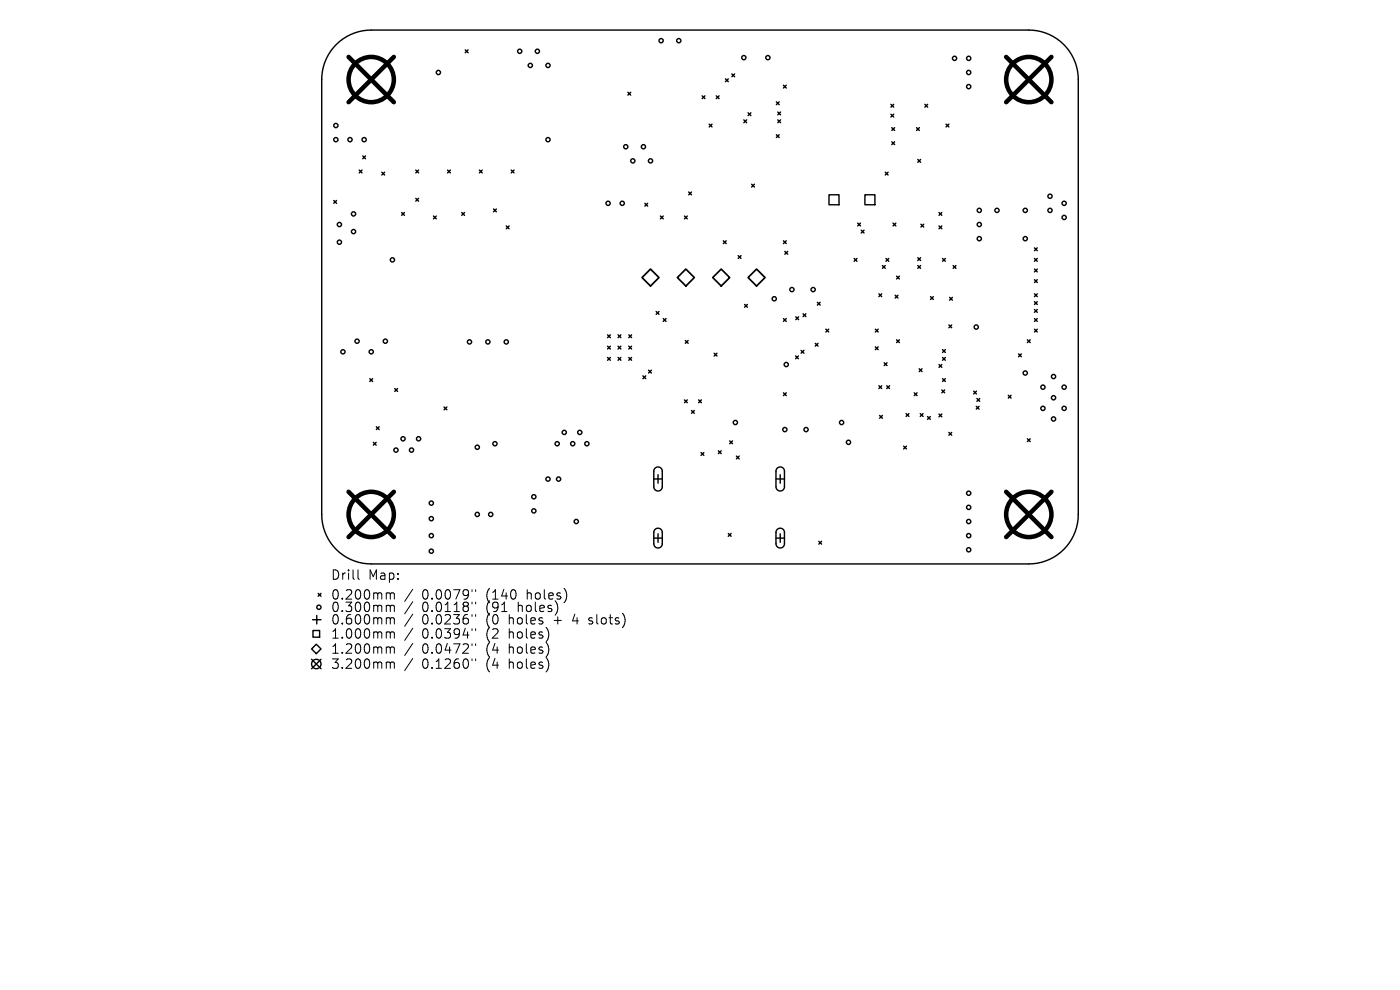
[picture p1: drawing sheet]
<svg xmlns="http://www.w3.org/2000/svg" width="297mm" height="210mm" viewBox="0 0 297 210" stroke-linecap="round" stroke-linejoin="round" font-family="sans-serif">
<defs><g id="words">
<g font-size="2.8">
<text x="70.1" y="123.3">Drill</text>
<text x="78.1" y="123.3">Map:</text>
<text x="70.1" y="127.5">0.200mm</text>
<text x="70.1" y="130.1">0.300mm</text>
<text x="89.5" y="127.5">0.0079&quot;</text>
<text x="89.5" y="130.1">0.0118&quot;</text>
<text x="103.3" y="127.5">(140</text>
<text x="103.3" y="130.1">(91</text>
<text x="110.1" y="130.1">holes)</text>
<text x="112" y="127.5">holes)</text>
<text x="70.1" y="132.8">0.600mm</text>
<text x="70.1" y="135.8">1.000mm</text>
<text x="89.5" y="132.8">0.0236&quot;</text>
<text x="89.5" y="135.8">0.0394&quot;</text>
<text x="103.3" y="132.8">(0</text>
<text x="103.3" y="135.8">(2</text>
<text x="108.2" y="132.8">holes</text>
<text x="108.2" y="135.8">holes)</text>
<text x="118" y="132.8">+</text>
<text x="122.2" y="132.8">4</text>
<text x="125.8" y="132.8">slots)</text>
<text x="70.1" y="139">1.200mm</text>
<text x="70.1" y="142.2">3.200mm</text>
<text x="89.5" y="139">0.0472&quot;</text>
<text x="89.5" y="142.2">0.1260&quot;</text>
<text x="103.3" y="139">(4</text>
<text x="103.3" y="142.2">(4</text>
<text x="108.2" y="139">holes)</text>
<text x="108.2" y="142.2">holes)</text>
</g>
</g></defs>
<g fill="none" stroke="#000" stroke-width=".3">
<path d="M71.3 9.5a10.5 10.5 0 0 1 7.5-3.1h139.5a10.5 10.5 0 0 1 10.5 10.5v92.2a10.5 10.5 0 0 1-10.5 10.5h-139.5a10.5 10.5 0 0 1-10.5-10.5v-92.2a10.5 10.5 0 0 1 3-7.4zM98.7 10.6l.6 .6M99.3 10.6l-.6 .6M133.2 19.6l.6 .6M133.8 19.6l-.6 .6M153.9 16.7l.6 .6M154.5 16.7l-.6 .6M155.3 15.7l.6 .6M155.9 15.7l-.6 .6M166.2 18.1l.6 .6M166.8 18.1l-.6 .6M76.2 36.1l.6 .6"/>
<path d="M76.8 36.1l-.6 .6M77 33.1l.6 .6M77.6 33.1l-.6 .6M81 36.5l.6 .6M81.6 36.5l-.6 .6M88.2 36.1l.6 .6M88.8 36.1l-.6 .6M95 36.1l.6 .6M95.6 36.1l-.6 .6M101.7 36.1l.6 .6M102.3 36.1l-.6 .6M108.5 36.1l.6 .6"/>
<path d="M109.1 36.1l-.6 .6M149 20.3l.6 .6M149.6 20.3l-.6 .6M150.5 26.3l.6 .6M151.1 26.3l-.6 .6M152 20.3l.6 .6M152.6 20.3l-.6 .6M157.8 25.4l.6 .6M158.4 25.4l-.6 .6M158.7 23.9l.6 .6M159.3 23.9l-.6 .6M159.5 39.1l.6 .6"/>
<path d="M160.1 39.1l-.6 .6M164.7 21.6l.6 .6M164.7 28.6l.6 .6M165 23.8l.6 .6M165 25.4l.6 .6M165.3 21.6l-.6 .6M165.3 28.6l-.6 .6M165.6 23.8l-.6 .6M165.6 25.4l-.6 .6M187.8 36.5l.6 .6M188.4 36.5l-.6 .6M189 22.1l.6 .6"/>
<path d="M189 24.2l.6 .6M189.2 27.1l.6 .6M189.2 30.1l.6 .6M189.6 22.1l-.6 .6M189.6 24.2l-.6 .6M189.8 27.1l-.6 .6M189.8 30.1l-.6 .6M194.4 27.1l.6 .6M194.7 33.8l.6 .6M195 27.1l-.6 .6M195.3 33.8l-.6 .6M196.2 22.1l.6 .6"/>
<path d="M196.8 22.1l-.6 .6M200.7 26.3l.6 .6M201.3 26.3l-.6 .6M70.8 42.5l.6 .6M71.4 42.5l-.6 .6M85.2 45.1l.6 .6M85.8 45.1l-.6 .6M88.2 42.1l.6 .6M88.8 42.1l-.6 .6M92 45.8l.6 .6M92.6 45.8l-.6 .6M98 45.1l.6 .6"/>
<path d="M98.6 45.1l-.6 .6M104.7 44.3l.6 .6M105.3 44.3l-.6 .6M107.4 47.9l.6 .6M108 47.9l-.6 .6M136.8 43.1l.6 .6M137.4 43.1l-.6 .6M140.1 45.8l.6 .6M140.7 45.8l-.6 .6M145.2 45.8l.6 .6M145.8 45.8l-.6 .6M146.1 40.7l.6 .6"/>
<path d="M146.7 40.7l-.6 .6M153.5 51.1l.6 .6M154.1 51.1l-.6 .6M156.6 54.2l.6 .6M157.2 54.2l-.6 .6M166.2 51.1l.6 .6M166.5 53.3l.6 .6M166.8 51.1l-.6 .6M167.1 53.3l-.6 .6M175.9 41.3h2.1v2.1h-2.1zM181.2 54.8l.6 .6M181.8 54.8l-.6 .6"/>
<path d="M182 47.3l.6 .6M182.6 47.3l-.6 .6M182.7 48.8l.6 .6M183.3 48.8l-.6 .6M183.5 41.3h2.1v2.1h-2.1zM187.2 56.3l.6 .6M187.8 56.3l-.6 .6M188 54.8l.6 .6M188.6 54.8l-.6 .6M189.5 47.3l.6 .6M190.1 47.3l-.6 .6M190.2 58.6l.6 .6"/>
<path d="M190.8 58.6l-.6 .6M194.7 54.7l.6 .6M194.7 56.3l.6 .6M195.3 54.7l-.6 .6M195.3 56.3l-.6 .6M195.4 47.6l.6 .6M196 47.6l-.6 .6M199.2 45.1l.6 .6M199.2 47.9l.6 .6M199.8 45.1l-.6 .6M199.8 47.9l-.6 .6M200 54.8l.6 .6"/>
<path d="M200.6 54.8l-.6 .6M202.2 56.3l.6 .6M202.8 56.3l-.6 .6M219.5 52.6l.6 .6M219.5 54.8l.6 .6M219.5 57.1l.6 .6M219.5 59.3l.6 .6M220.1 57.1l-.6 .6M220.1 52.6l-.6 .6M220.1 54.8l-.6 .6M220.1 59.3l-.6 .6M128.9 71l.6 .6"/>
<path d="M128.9 73.4l.6 .6M128.9 75.8l.6 .6M129.5 71l-.6 .6M129.5 73.4l-.6 .6M129.5 75.8l-.6 .6M131.1 71l.6 .6M131.1 73.4l.6 .6M131.1 75.8l.6 .6M131.7 71l-.6 .6M131.7 73.4l-.6 .6M131.7 75.8l-.6 .6M133.4 71l.6 .6"/>
<path d="M133.4 73.4l.6 .6M133.4 75.8l.6 .6M134 71l-.6 .6M134 73.4l-.6 .6M134 75.8l-.6 .6M136.4 79.7l.6 .6M137 79.7l-.6 .6M137.6 78.5l.6 .6M138.2 78.5l-.6 .6M139.2 66.1l.6 .6M139.8 66.1l-.6 .6M140.7 67.6l.6 .6"/>
<path d="M141.3 67.6l-.6 .6M145.4 72.2l.6 .6M146 72.2l-.6 .6M151.5 74.9l.6 .6M152.1 74.9l-.6 .6M158 64.6l.6 .6M158.6 64.6l-.6 .6M166.2 67.6l.6 .6M166.8 67.6l-.6 .6M168.8 75.5l.6 .6M168.8 67.2l.6 .6M169.4 75.5l-.6 .6"/>
<path d="M169.4 67.2l-.6 .6M170 74.3l.6 .6M170.4 66.6l.6 .6M170.6 74.3l-.6 .6M171 66.6l-.6 .6M173 72.8l.6 .6M173.4 64.1l.6 .6M173.6 72.8l-.6 .6M174 64.1l-.6 .6M175.2 69.8l.6 .6M175.8 69.8l-.6 .6M185.7 69.8l.6 .6"/>
<path d="M185.7 73.6l.6 .6M186.3 69.8l-.6 .6M186.3 73.6l-.6 .6M186.5 62.3l.6 .6M187.1 62.3l-.6 .6M187.6 77l.6 .6M188.2 77l-.6 .6M189.9 62.6l.6 .6M190.2 72.1l.6 .6M190.5 62.6l-.6 .6M190.8 72.1l-.6 .6M195 78.2l.6 .6"/>
<path d="M195.6 78.2l-.6 .6M197.4 62.9l.6 .6M198 62.9l-.6 .6M199.2 77.3l.6 .6M199.8 77.3l-.6 .6M200 75.8l.6 .6M200 74.2l.6 .6M200.6 74.2l-.6 .6M200.6 75.8l-.6 .6M201.3 68.9l.6 .6M201.5 63.1l.6 .6M201.9 68.9l-.6 .6"/>
<path d="M202.1 63.1l-.6 .6M216.1 75.1l.6 .6M216.7 75.1l-.6 .6M218 72.1l.6 .6M218.6 72.1l-.6 .6M219.5 62.3l.6 .6M219.5 64l.6 .6M219.5 65.7l.6 .6M219.5 67.6l.6 .6M219.5 69.8l.6 .6M220.1 65.7l-.6 .6M220.1 67.6l-.6 .6"/>
<path d="M220.1 62.3l-.6 .6M220.1 64l-.6 .6M220.1 69.8l-.6 .6M78.5 80.3l.6 .6M79.1 80.3l-.6 .6M79.2 93.8l.6 .6M79.8 93.8l-.6 .6M79.8 90.5l.6 .6M80.4 90.5l-.6 .6M83.7 82.4l.6 .6M84.3 82.4l-.6 .6M94.2 86.3l.6 .6"/>
<path d="M94.8 86.3l-.6 .6M139 99.3a.9 .9 0 0 1 .9-.2 .9 .9 0 0 1 .6 .9v3.3a.9 .9 0 0 1-.9 .9 .9 .9 0 0 1-.9-.9v-3.4zM145.2 84.8l.6 .6M145.8 84.8l-.6 .6M146.7 87.1l.6 .6M147.3 87.1l-.6 .6M148.2 84.8l.6 .6M148.7 96l.6 .6M148.8 84.8l-.6 .6M149.3 96l-.6 .6M152.4 95.6l.6 .6M153 95.6l-.6 .6"/>
<path d="M154.8 93.5l.6 .6M155.4 93.5l-.6 .6M156.2 96.7l.6 .6M156.8 96.7l-.6 .6M164.9 99.3a.9 .9 0 0 1 1-.2 .9 .9 0 0 1 .5 .9v3.3a.9 .9 0 0 1-.9 .9 .9 .9 0 0 1-.9-.9v-3.4zM166.2 83.3l.6 .6M166.8 83.3l-.6 .6M186.5 81.8l.6 .6M186.6 88.1l.6 .6M187.1 81.8l-.6 .6M187.2 88.1l-.6 .6M188.1 81.8l.6 .6"/>
<path d="M188.7 81.8l-.6 .6M191.7 94.6l.6 .6M192.2 87.7l.6 .6M192.3 94.6l-.6 .6M192.8 87.7l-.6 .6M194 83.3l.6 .6M194.6 83.3l-.6 .6M195.2 87.7l.6 .6M195.8 87.7l-.6 .6M196.8 88.4l.6 .6M197.4 88.4l-.6 .6M199.2 87.8l.6 .6"/>
<path d="M199.8 87.8l-.6 .6M199.8 82.7l.6 .6M200 80.3l.6 .6M200.4 82.7l-.6 .6M200.6 80.3l-.6 .6M201.3 91.7l.6 .6M201.9 91.7l-.6 .6M206.6 83l.6 .6M207.1 86.2l.6 .6M207.2 83l-.6 .6M207.2 84.5l.6 .6M207.7 86.2l-.6 .6"/>
<path d="M207.8 84.5l-.6 .6M213.9 83.9l.6 .6M214.5 83.9l-.6 .6M218 93.1l.6 .6M218.6 93.1l-.6 .6M138.7 101.6h1.8M138.7 114.1h1.8M139 112.3a.9 .9 0 0 1 .9-.2 .9 .9 0 0 1 .6 .8v2.4a.9 .9 0 0 1-.9 .9 .9 .9 0 0 1-.9-.9v-2.4zM139.6 100.7v1.8M139.6 113.2v1.8M154.5 113.2l.6 .6M155.1 113.2l-.6 .6"/>
<path d="M164.6 101.6h1.8M164.6 114.1h1.8M164.9 112.3a.9 .9 0 0 1 1-.2 .9 .9 0 0 1 .5 .8v2.4a.9 .9 0 0 1-.9 .9 .9 .9 0 0 1-.9-.9v-2.4zM165.5 100.7v1.8M165.5 113.2v1.8M173.7 114.8l.6 .6M174.3 114.8l-.6 .6M66.1 139.9l2 2M66.3 131.5h1.8M66.4 133.8h1.4v1.4h-1.4zM67.1 136.7l1 1-1 1-1-1zM67.2 130.6v1.8"/>
<path d="M67.5 125.9l.6 .6M68.1 125.9l-.6 .6M68.1 139.9l-2 2"/>
<circle cx="93" cy="15.4" r=".45"/>
<circle cx="110.3" cy="10.9" r=".45"/>
<circle cx="112.5" cy="13.9" r=".45"/>
<circle cx="114" cy="10.9" r=".45"/>
<circle cx="116.3" cy="13.9" r=".45"/>
<circle cx="140.3" cy="8.6" r=".45"/>
<circle cx="144" cy="8.6" r=".45"/>
<circle cx="157.8" cy="12.2" r=".45"/>
<circle cx="162.9" cy="12.2" r=".45"/>
<circle cx="202.5" cy="12.4" r=".45"/>
<circle cx="205.5" cy="18.4" r=".45"/>
<circle cx="205.5" cy="12.4" r=".45"/>
<circle cx="205.5" cy="15.4" r=".45"/>
<circle cx="71.3" cy="26.6" r=".45"/>
<circle cx="71.3" cy="29.6" r=".45"/>
<circle cx="74.3" cy="29.6" r=".45"/>
<circle cx="77.3" cy="29.6" r=".45"/>
<circle cx="116.3" cy="29.6" r=".45"/>
<circle cx="132.8" cy="31.1" r=".45"/>
<circle cx="134.3" cy="34.1" r=".45"/>
<circle cx="136.5" cy="31.1" r=".45"/>
<circle cx="138" cy="34.1" r=".45"/>
<circle cx="72" cy="51.4" r=".45"/>
<circle cx="72" cy="47.6" r=".45"/>
<circle cx="75" cy="45.4" r=".45"/>
<circle cx="75" cy="49.1" r=".45"/>
<circle cx="83.3" cy="55.1" r=".45"/>
<circle cx="129" cy="43.1" r=".45"/>
<circle cx="132" cy="43.1" r=".45"/>
<circle cx="207.8" cy="44.6" r=".45"/>
<circle cx="207.8" cy="50.6" r=".45"/>
<circle cx="207.8" cy="47.6" r=".45"/>
<circle cx="211.5" cy="44.6" r=".45"/>
<circle cx="217.5" cy="44.6" r=".45"/>
<circle cx="217.5" cy="50.6" r=".45"/>
<circle cx="222.8" cy="44.6" r=".45"/>
<circle cx="222.8" cy="41.6" r=".45"/>
<circle cx="225.8" cy="43.1" r=".45"/>
<circle cx="225.8" cy="46.1" r=".45"/>
<circle cx="72.8" cy="74.6" r=".45"/>
<circle cx="75.8" cy="72.4" r=".45"/>
<circle cx="78.8" cy="74.6" r=".45"/>
<circle cx="81.8" cy="72.4" r=".45"/>
<circle cx="99.6" cy="72.5" r=".45"/>
<circle cx="103.5" cy="72.5" r=".45"/>
<circle cx="107.4" cy="72.5" r=".45"/>
<circle cx="164.3" cy="63.4" r=".45"/>
<circle cx="166.8" cy="77.3" r=".45"/>
<circle cx="168" cy="61.4" r=".45"/>
<circle cx="172.5" cy="61.4" r=".45"/>
<circle cx="207.1" cy="69.4" r=".45"/>
<circle cx="217.5" cy="79.1" r=".45"/>
<circle cx="223.5" cy="79.9" r=".45"/>
<circle cx="84" cy="95.5" r=".45"/>
<circle cx="85.5" cy="93.1" r=".45"/>
<circle cx="87.3" cy="95.5" r=".45"/>
<circle cx="88.8" cy="93.1" r=".45"/>
<circle cx="101.3" cy="94.9" r=".45"/>
<circle cx="105" cy="94.1" r=".45"/>
<circle cx="118.2" cy="94.1" r=".45"/>
<circle cx="119.7" cy="91.7" r=".45"/>
<circle cx="121.5" cy="94.1" r=".45"/>
<circle cx="123" cy="91.7" r=".45"/>
<circle cx="124.5" cy="94.1" r=".45"/>
<circle cx="156" cy="89.6" r=".45"/>
<circle cx="166.5" cy="91.1" r=".45"/>
<circle cx="171" cy="91.1" r=".45"/>
<circle cx="178.5" cy="89.6" r=".45"/>
<circle cx="180" cy="93.8" r=".45"/>
<circle cx="221.3" cy="86.6" r=".45"/>
<circle cx="221.3" cy="82.1" r=".45"/>
<circle cx="223.5" cy="84.4" r=".45"/>
<circle cx="223.5" cy="88.9" r=".45"/>
<circle cx="225.8" cy="82.1" r=".45"/>
<circle cx="225.8" cy="86.6" r=".45"/>
<circle cx="91.5" cy="110" r=".45"/>
<circle cx="91.5" cy="106.7" r=".45"/>
<circle cx="91.5" cy="116.9" r=".45"/>
<circle cx="91.5" cy="113.6" r=".45"/>
<circle cx="101.3" cy="109.1" r=".45"/>
<circle cx="104.1" cy="109.1" r=".45"/>
<circle cx="113.3" cy="105.4" r=".45"/>
<circle cx="113.3" cy="108.4" r=".45"/>
<circle cx="116.3" cy="101.6" r=".45"/>
<circle cx="118.5" cy="101.6" r=".45"/>
<circle cx="122.3" cy="110.6" r=".45"/>
<circle cx="205.5" cy="104.6" r=".45"/>
<circle cx="205.5" cy="116.6" r=".45"/>
<circle cx="205.5" cy="110.6" r=".45"/>
<circle cx="205.5" cy="107.6" r=".45"/>
<circle cx="205.5" cy="113.6" r=".45"/>
<circle cx="67.7" cy="128.8" r=".45"/>
<circle cx="67.1" cy="140.9" r="1"/>
</g>
<path d="M138 57.1l1.8 1.8-1.8 1.8-1.8-1.8zM145.5 57.1l1.8 1.8-1.8 1.8-1.8-1.8zM153 57.1l1.8 1.8-1.8 1.8-1.8-1.8zM160.5 57.1l1.8 1.8-1.8 1.8-1.8-1.8z" fill="none" stroke="#000" stroke-width=".36"/>
<g fill="none" stroke="#000" stroke-width=".96">
<path d="M74 12.1l9.6 9.6M83.6 12.1l-9.6 9.6M213.5 12.1l9.6 9.6M223.1 12.1l-9.6 9.6M74 104.3l9.6 9.6M83.6 104.3l-9.6 9.6M213.5 104.3l9.6 9.6M223.1 104.3l-9.6 9.6"/>
<circle cx="78.8" cy="16.9" r="4.8"/>
<circle cx="218.3" cy="16.9" r="4.8"/>
<circle cx="78.8" cy="109.1" r="4.8"/>
<circle cx="218.3" cy="109.1" r="4.8"/>
</g>
<g fill="none" stroke="#000" stroke-width=".21">
<path d="M75.9 120.9v1.7l.3 .3M82.2 125.8l.5 .1 .1 .1M82.2 128.4l.5 .1 .1 .2M82.2 131l.5 .1 .1 .2M82.2 134l.5 .1 .1 .2M82.2 137.2l.5 .1 .1 .2M82.8 126l.3-.2 .5 .1 .1 1.2M82.8 126v1.1M82.8 128.7v1M82.8 131.3v1.1M82.8 134.3v1.1M82.8 137.5v1.1"/>
<path d="M82.8 128.7l.3-.3 .5 .1 .1 1.2M82.8 131.3l.3-.3 .5 .1 .1 1.3M82.8 134.3l.3-.3 .5 .1 .1 1.3M82.8 137.5l.3-.3 .5 .1 .1 1.3M87.6 125l-1.7 2.6M87.6 127.6l-1.7 2.6M87.6 130.3l-1.7 2.5M87.6 133.3l-1.7 2.5M87.6 136.5l-1.7 2.5M87.6 139.7l-1.7 2.5M100.1 125.1v.4M100.1 127.7v.4"/>
<path d="M100.1 130.4v.4M100.1 133.4v.4M100.1 136.6v.4M100.1 139.8v.4M100.9 125.1v.4M100.9 127.7v.4M100.9 130.4v.4M100.9 133.4v.4M100.9 136.6v.4M100.9 139.8v.4M124.9 132.3l.2 .1M125 131.1v.5"/>
<path d="M82.2 140.4l.5 .1 .1 .2M82.8 140.7v1.1M82.8 140.7l.3-.3 .5 .1 .1 1.3"/>
</g>
<use href="#words"/>
</svg>
